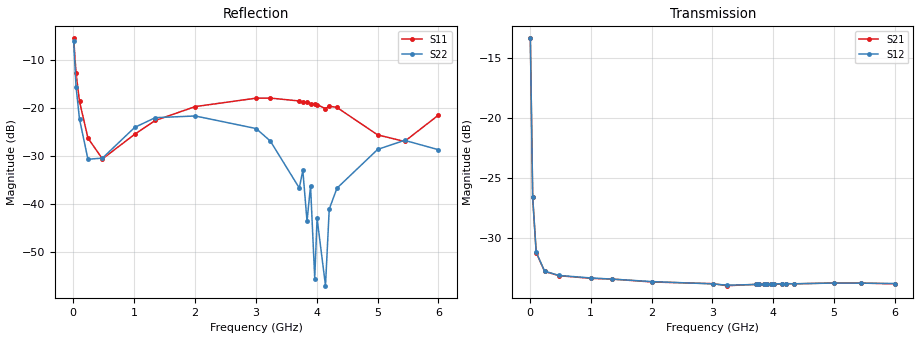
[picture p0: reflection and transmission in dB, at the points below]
!Agilent Technologies,E5071C,MY46316741,A.11.02
!Date: Thu Jul 30 16:15:13 2020
!Data & Calibration Information:
!Freq	S11:SOLT4(ON)	S21:SOLT4(ON)	S12:SOLT4(ON)	S22:SOLT4(ON)
!PortZ  Port1:50+j0  Port2:50+j0
!Above PortZ is port z conversion or system Z0 setting when saving the data.
!When reading, reference impedance value at option line is always used.
# Hz S dB R 50
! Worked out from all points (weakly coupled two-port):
!   1561 points, 10 MHz to 6 GHz, reference 50 ohm
!   highest |S21| = -13.35 dB at 10 MHz (marker M1); lowest = -33.9 dB at 3.239 GHz (marker M2)
!   lowest |S11| = -30.6 dB at 482.3 MHz (marker M3), VSWR 1.06, Z = 47.6 + j1.57 ohm
!   |S11| at or under -10 dB: 30.64 MHz to end of sweep
!   |S22| runs from -60.3 to -6.2 dB; largest |S21 - S12| = 0.00041
!   S11 on the Smith chart (normalised r, x): 10 MHz: 1.87, -1.45; 48.4 MHz: 1.03, -0.48; 1.35 GHz: 1.15, +0.06; 6 GHz: 0.95, -0.16
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1e7  -5.59 -32.2  -13.35 -50.0  -13.35 -50.1  -6.20 -41.0
4.839744e7  -12.76 -73.2  -26.58 -69.1  -26.59 -69.1  -15.61 -85.1
1.059936e8  -18.71 -98.2  -31.19 -52.1  -31.15 -52.0  -22.39 -109.9
2.442244e8  -26.31 -139.2  -32.75 -48.1  -32.73 -48.1  -30.71 -164.5
4.822885e8  -30.64 145.9  -33.11 -67.5  -33.09 -67.5  -30.48 102.7
1.012173e9  -25.52 55.1  -33.33 -125.4  -33.30 -125.5  -24.09 26.8
1.350071e9  -22.65 21.3  -33.39 -164.4  -33.39 -164.6  -22.07 -6.0
2.006667e9  -19.77 -29.5  -33.63 119.6  -33.60 119.5  -21.72 -64.9
3.005e9  -18.02 -105.0  -33.77 3.1  -33.79 2.4  -24.33 -142.7
3.239224e9  -18.00 -122.7  -33.94 -23.9  -33.90 -24.5  -26.92 -162.1
3.715353e9  -18.60 -163.3  -33.83 -78.8  -33.84 -79.3  -36.70 156.4
3.772949e9  -18.80 -167.5  -33.82 -85.4  -33.84 -86.2  -33.01 151.9
3.842064e9  -18.91 -174.7  -33.82 -93.7  -33.83 -94.3  -43.59 136.3
3.89966e9  -19.16 -178.1  -33.81 -100.4  -33.82 -100.9  -36.24 140.9
3.968776e9  -19.14 173.9  -33.82 -108.4  -33.82 -108.9  -55.51 68.3
4.007173e9  -19.35 172.8  -33.81 -112.9  -33.80 -113.7  -42.99 99.6
4.145404e9  -20.20 160.0  -33.80 -129.0  -33.77 -129.6  -56.99 -12.6
4.20684e9  -19.68 152.0  -33.77 -136.3  -33.77 -137.0  -41.07 -60.9
4.333551e9  -19.95 140.4  -33.79 -151.3  -33.78 -152.0  -36.73 -68.7
5.001667e9  -25.65 56.7  -33.71 130.9  -33.72 130.1  -28.67 -137.0
5.443237e9  -27.01 -22.9  -33.72 79.3  -33.73 78.4  -26.78 -161.7
6e9  -21.55 -102.0  -33.79 15.2  -33.76 14.2  -28.73 140.5
